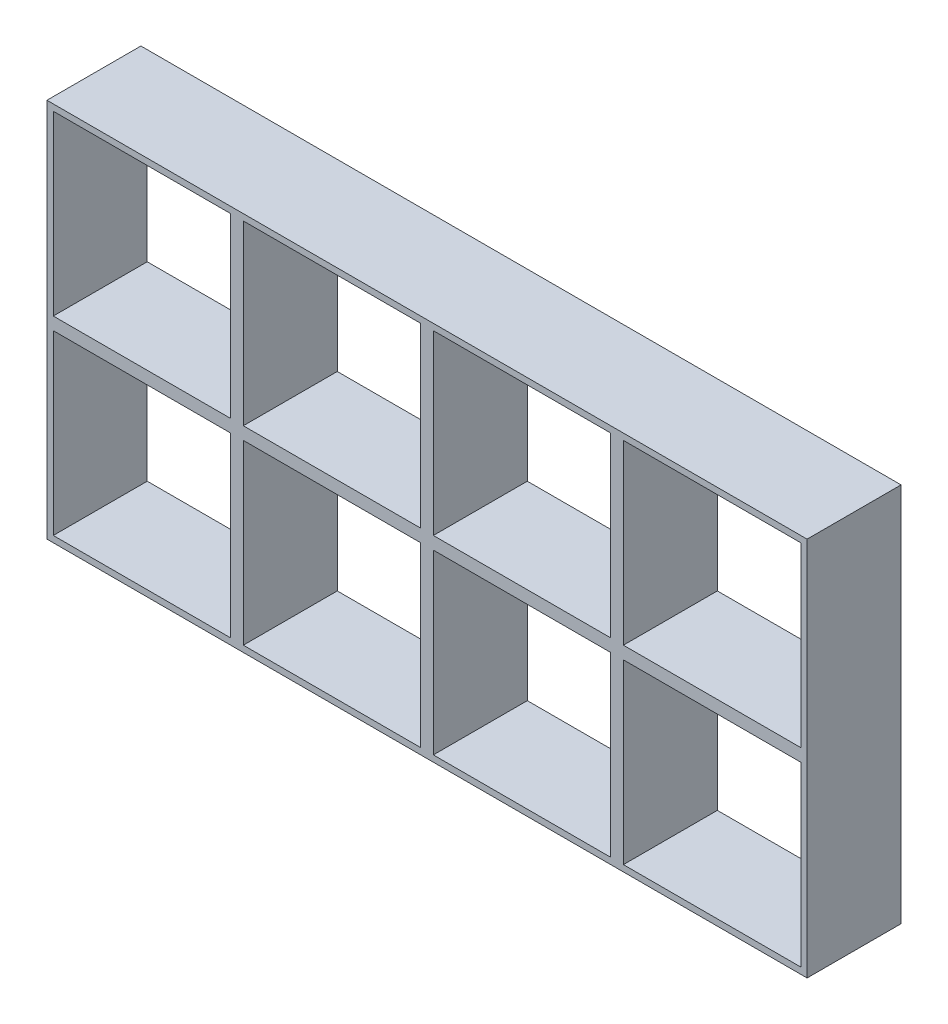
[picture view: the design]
ISO-10303-21;
HEADER;
FILE_DESCRIPTION(('STEP AP214'),'2;1');
FILE_NAME('part.step','',(''),(''),'','','');
FILE_SCHEMA(('AUTOMOTIVE_DESIGN { 1 0 10303 214 1 1 1 1 }'));
ENDSEC;
DATA;
#1=APPLICATION_CONTEXT('core data for automotive mechanical design processes');
#2=APPLICATION_PROTOCOL_DEFINITION('international standard','automotive_design',2000,#1);
#3=PRODUCT_CONTEXT('',#1,'mechanical');
#4=PRODUCT('Part','Part','',(#3));
#5=PRODUCT_RELATED_PRODUCT_CATEGORY('part','',(#4));
#6=PRODUCT_DEFINITION_FORMATION('','',#4);
#7=PRODUCT_DEFINITION_CONTEXT('part definition',#1,'design');
#8=PRODUCT_DEFINITION('design','',#6,#7);
#9=PRODUCT_DEFINITION_SHAPE('','',#8);
#10=(LENGTH_UNIT() NAMED_UNIT(*) SI_UNIT(.MILLI.,.METRE.));
#11=(NAMED_UNIT(*) PLANE_ANGLE_UNIT() SI_UNIT($,.RADIAN.));
#12=(NAMED_UNIT(*) SI_UNIT($,.STERADIAN.) SOLID_ANGLE_UNIT());
#13=UNCERTAINTY_MEASURE_WITH_UNIT(LENGTH_MEASURE(1.E-05),#10,'distance_accuracy_value','');
#14=(GEOMETRIC_REPRESENTATION_CONTEXT(3) GLOBAL_UNCERTAINTY_ASSIGNED_CONTEXT((#13)) GLOBAL_UNIT_ASSIGNED_CONTEXT((#10,
#11,#12)) REPRESENTATION_CONTEXT('',''));
#15=CARTESIAN_POINT('',(0.,0.,0.));
#16=DIRECTION('',(0.,0.,1.));
#17=DIRECTION('',(1.,0.,0.));
#18=AXIS2_PLACEMENT_3D('',#15,#16,#17);
#19=CARTESIAN_POINT('',(0.,0.,14.8333333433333));
#20=DIRECTION('',(-1.,0.,0.));
#21=DIRECTION('',(0.,0.,1.));
#22=AXIS2_PLACEMENT_3D('',#19,#20,#21);
#23=PLANE('',#22);
#24=DIRECTION('',(0.,1.,0.));
#25=VECTOR('',#24,1.);
#26=CARTESIAN_POINT('',(0.,0.,0.));
#27=LINE('',#26,#25);
#28=CARTESIAN_POINT('',(0.,-30.,0.));
#29=VERTEX_POINT('',#28);
#30=CARTESIAN_POINT('',(0.,30.,0.));
#31=VERTEX_POINT('',#30);
#32=EDGE_CURVE('E297',#29,#31,#27,.T.);
#33=ORIENTED_EDGE('',*,*,#32,.F.);
#34=DIRECTION('',(0.,0.,-1.));
#35=VECTOR('',#34,1.);
#36=CARTESIAN_POINT('',(0.,-30.,14.8333333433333));
#37=LINE('',#36,#35);
#38=CARTESIAN_POINT('',(0.,-30.,14.8333333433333));
#39=VERTEX_POINT('',#38);
#40=EDGE_CURVE('E240',#39,#29,#37,.T.);
#41=ORIENTED_EDGE('',*,*,#40,.F.);
#42=DIRECTION('',(0.,1.,0.));
#43=VECTOR('',#42,1.);
#44=CARTESIAN_POINT('',(0.,0.,14.8333333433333));
#45=LINE('',#44,#43);
#46=CARTESIAN_POINT('',(0.,30.,14.8333333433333));
#47=VERTEX_POINT('',#46);
#48=EDGE_CURVE('E218',#39,#47,#45,.T.);
#49=ORIENTED_EDGE('',*,*,#48,.T.);
#50=DIRECTION('',(0.,0.,-1.));
#51=VECTOR('',#50,1.);
#52=CARTESIAN_POINT('',(0.,30.,14.8333333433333));
#53=LINE('',#52,#51);
#54=EDGE_CURVE('E62',#47,#31,#53,.T.);
#55=ORIENTED_EDGE('',*,*,#54,.T.);
#56=EDGE_LOOP('',(#33,#41,#49,#55));
#57=FACE_BOUND('',#56,.T.);
#58=ADVANCED_FACE('F51',(#57),#23,.T.);
#59=CARTESIAN_POINT('',(120.,0.,14.8333333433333));
#60=DIRECTION('',(-1.,0.,0.));
#61=DIRECTION('',(0.,-1.,0.));
#62=AXIS2_PLACEMENT_3D('',#59,#60,#61);
#63=PLANE('',#62);
#64=DIRECTION('',(0.,1.,0.));
#65=VECTOR('',#64,1.);
#66=CARTESIAN_POINT('',(120.,0.,0.));
#67=LINE('',#66,#65);
#68=CARTESIAN_POINT('',(120.,-30.,0.));
#69=VERTEX_POINT('',#68);
#70=CARTESIAN_POINT('',(120.,30.,0.));
#71=VERTEX_POINT('',#70);
#72=EDGE_CURVE('E300',#69,#71,#67,.T.);
#73=ORIENTED_EDGE('',*,*,#72,.T.);
#74=DIRECTION('',(0.,0.,-1.));
#75=VECTOR('',#74,1.);
#76=CARTESIAN_POINT('',(120.,30.,14.8333333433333));
#77=LINE('',#76,#75);
#78=CARTESIAN_POINT('',(120.,30.,14.8333333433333));
#79=VERTEX_POINT('',#78);
#80=EDGE_CURVE('E11',#79,#71,#77,.T.);
#81=ORIENTED_EDGE('',*,*,#80,.F.);
#82=DIRECTION('',(0.,1.,0.));
#83=VECTOR('',#82,1.);
#84=CARTESIAN_POINT('',(120.,0.,14.8333333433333));
#85=LINE('',#84,#83);
#86=CARTESIAN_POINT('',(120.,-30.,14.8333333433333));
#87=VERTEX_POINT('',#86);
#88=EDGE_CURVE('E223',#87,#79,#85,.T.);
#89=ORIENTED_EDGE('',*,*,#88,.F.);
#90=DIRECTION('',(0.,0.,-1.));
#91=VECTOR('',#90,1.);
#92=CARTESIAN_POINT('',(120.,-30.,14.8333333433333));
#93=LINE('',#92,#91);
#94=EDGE_CURVE('E488',#87,#69,#93,.T.);
#95=ORIENTED_EDGE('',*,*,#94,.T.);
#96=EDGE_LOOP('',(#73,#81,#89,#95));
#97=FACE_BOUND('',#96,.T.);
#98=ADVANCED_FACE('F743',(#97),#63,.F.);
#99=CARTESIAN_POINT('',(0.,1.,14.8333333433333));
#100=DIRECTION('',(0.,1.,0.));
#101=DIRECTION('',(0.,0.,1.));
#102=AXIS2_PLACEMENT_3D('',#99,#100,#101);
#103=PLANE('',#102);
#104=DIRECTION('',(1.,0.,0.));
#105=VECTOR('',#104,1.);
#106=CARTESIAN_POINT('',(0.,1.,0.));
#107=LINE('',#106,#105);
#108=CARTESIAN_POINT('',(1.,1.,0.));
#109=VERTEX_POINT('',#108);
#110=CARTESIAN_POINT('',(29.,1.,0.));
#111=VERTEX_POINT('',#110);
#112=EDGE_CURVE('E284',#109,#111,#107,.T.);
#113=ORIENTED_EDGE('',*,*,#112,.F.);
#114=DIRECTION('',(0.,0.,-1.));
#115=VECTOR('',#114,1.);
#116=CARTESIAN_POINT('',(1.,1.,14.8333333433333));
#117=LINE('',#116,#115);
#118=CARTESIAN_POINT('',(1.,1.,14.8333333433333));
#119=VERTEX_POINT('',#118);
#120=EDGE_CURVE('E204',#119,#109,#117,.T.);
#121=ORIENTED_EDGE('',*,*,#120,.F.);
#122=DIRECTION('',(1.,0.,0.));
#123=VECTOR('',#122,1.);
#124=CARTESIAN_POINT('',(0.,1.,14.8333333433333));
#125=LINE('',#124,#123);
#126=CARTESIAN_POINT('',(29.,1.,14.8333333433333));
#127=VERTEX_POINT('',#126);
#128=EDGE_CURVE('E202',#119,#127,#125,.T.);
#129=ORIENTED_EDGE('',*,*,#128,.T.);
#130=DIRECTION('',(0.,0.,-1.));
#131=VECTOR('',#130,1.);
#132=CARTESIAN_POINT('',(29.,1.,14.8333333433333));
#133=LINE('',#132,#131);
#134=EDGE_CURVE('E187',#127,#111,#133,.T.);
#135=ORIENTED_EDGE('',*,*,#134,.T.);
#136=EDGE_LOOP('',(#113,#121,#129,#135));
#137=FACE_BOUND('',#136,.T.);
#138=ADVANCED_FACE('F203',(#137),#103,.T.);
#139=CARTESIAN_POINT('',(1.,0.,14.8333333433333));
#140=DIRECTION('',(1.,0.,0.));
#141=DIRECTION('',(0.,1.,0.));
#142=AXIS2_PLACEMENT_3D('',#139,#140,#141);
#143=PLANE('',#142);
#144=DIRECTION('',(0.,-1.,0.));
#145=VECTOR('',#144,1.);
#146=CARTESIAN_POINT('',(1.,0.,0.));
#147=LINE('',#146,#145);
#148=CARTESIAN_POINT('',(1.,29.,0.));
#149=VERTEX_POINT('',#148);
#150=EDGE_CURVE('E287',#149,#109,#147,.T.);
#151=ORIENTED_EDGE('',*,*,#150,.F.);
#152=DIRECTION('',(0.,0.,-1.));
#153=VECTOR('',#152,1.);
#154=CARTESIAN_POINT('',(1.,29.,14.8333333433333));
#155=LINE('',#154,#153);
#156=CARTESIAN_POINT('',(1.,29.,14.8333333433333));
#157=VERTEX_POINT('',#156);
#158=EDGE_CURVE('E312',#157,#149,#155,.T.);
#159=ORIENTED_EDGE('',*,*,#158,.F.);
#160=DIRECTION('',(0.,-1.,0.));
#161=VECTOR('',#160,1.);
#162=CARTESIAN_POINT('',(1.,0.,14.8333333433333));
#163=LINE('',#162,#161);
#164=EDGE_CURVE('E209',#157,#119,#163,.T.);
#165=ORIENTED_EDGE('',*,*,#164,.T.);
#166=ORIENTED_EDGE('',*,*,#120,.T.);
#167=EDGE_LOOP('',(#151,#159,#165,#166));
#168=FACE_BOUND('',#167,.T.);
#169=ADVANCED_FACE('F414',(#168),#143,.T.);
#170=CARTESIAN_POINT('',(0.,29.,14.8333333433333));
#171=DIRECTION('',(0.,-1.,0.));
#172=DIRECTION('',(1.,0.,0.));
#173=AXIS2_PLACEMENT_3D('',#170,#171,#172);
#174=PLANE('',#173);
#175=DIRECTION('',(-1.,0.,0.));
#176=VECTOR('',#175,1.);
#177=CARTESIAN_POINT('',(0.,29.,0.));
#178=LINE('',#177,#176);
#179=CARTESIAN_POINT('',(29.,29.,0.));
#180=VERTEX_POINT('',#179);
#181=EDGE_CURVE('E291',#180,#149,#178,.T.);
#182=ORIENTED_EDGE('',*,*,#181,.F.);
#183=DIRECTION('',(0.,0.,-1.));
#184=VECTOR('',#183,1.);
#185=CARTESIAN_POINT('',(29.,29.,14.8333333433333));
#186=LINE('',#185,#184);
#187=CARTESIAN_POINT('',(29.,29.,14.8333333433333));
#188=VERTEX_POINT('',#187);
#189=EDGE_CURVE('E198',#188,#180,#186,.T.);
#190=ORIENTED_EDGE('',*,*,#189,.F.);
#191=DIRECTION('',(-1.,0.,0.));
#192=VECTOR('',#191,1.);
#193=CARTESIAN_POINT('',(0.,29.,14.8333333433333));
#194=LINE('',#193,#192);
#195=EDGE_CURVE('E216',#188,#157,#194,.T.);
#196=ORIENTED_EDGE('',*,*,#195,.T.);
#197=ORIENTED_EDGE('',*,*,#158,.T.);
#198=EDGE_LOOP('',(#182,#190,#196,#197));
#199=FACE_BOUND('',#198,.T.);
#200=ADVANCED_FACE('F417',(#199),#174,.T.);
#201=CARTESIAN_POINT('',(0.,0.999999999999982,14.8333333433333));
#202=DIRECTION('',(0.,1.,0.));
#203=DIRECTION('',(-1.,0.,0.));
#204=AXIS2_PLACEMENT_3D('',#201,#202,#203);
#205=PLANE('',#204);
#206=DIRECTION('',(1.,0.,0.));
#207=VECTOR('',#206,1.);
#208=CARTESIAN_POINT('',(0.,0.999999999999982,0.));
#209=LINE('',#208,#207);
#210=CARTESIAN_POINT('',(91.,1.00000000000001,0.));
#211=VERTEX_POINT('',#210);
#212=CARTESIAN_POINT('',(119.,1.00000000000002,0.));
#213=VERTEX_POINT('',#212);
#214=EDGE_CURVE('E268',#211,#213,#209,.T.);
#215=ORIENTED_EDGE('',*,*,#214,.F.);
#216=DIRECTION('',(0.,0.,-1.));
#217=VECTOR('',#216,1.);
#218=CARTESIAN_POINT('',(91.,1.00000000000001,14.8333333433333));
#219=LINE('',#218,#217);
#220=CARTESIAN_POINT('',(91.,1.00000000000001,14.8333333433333));
#221=VERTEX_POINT('',#220);
#222=EDGE_CURVE('E199',#221,#211,#219,.T.);
#223=ORIENTED_EDGE('',*,*,#222,.F.);
#224=DIRECTION('',(1.,0.,0.));
#225=VECTOR('',#224,1.);
#226=CARTESIAN_POINT('',(0.,0.999999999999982,14.8333333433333));
#227=LINE('',#226,#225);
#228=CARTESIAN_POINT('',(119.,1.00000000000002,14.8333333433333));
#229=VERTEX_POINT('',#228);
#230=EDGE_CURVE('E397',#221,#229,#227,.T.);
#231=ORIENTED_EDGE('',*,*,#230,.T.);
#232=DIRECTION('',(0.,0.,-1.));
#233=VECTOR('',#232,1.);
#234=CARTESIAN_POINT('',(119.,1.00000000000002,14.8333333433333));
#235=LINE('',#234,#233);
#236=EDGE_CURVE('E317',#229,#213,#235,.T.);
#237=ORIENTED_EDGE('',*,*,#236,.T.);
#238=EDGE_LOOP('',(#215,#223,#231,#237));
#239=FACE_BOUND('',#238,.T.);
#240=ADVANCED_FACE('F756',(#239),#205,.T.);
#241=CARTESIAN_POINT('',(91.,0.,14.8333333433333));
#242=DIRECTION('',(-1.,0.,0.));
#243=DIRECTION('',(0.,0.,1.));
#244=AXIS2_PLACEMENT_3D('',#241,#242,#243);
#245=PLANE('',#244);
#246=DIRECTION('',(0.,1.,0.));
#247=VECTOR('',#246,1.);
#248=CARTESIAN_POINT('',(91.,0.,0.));
#249=LINE('',#248,#247);
#250=CARTESIAN_POINT('',(91.,29.,0.));
#251=VERTEX_POINT('',#250);
#252=EDGE_CURVE('E272',#211,#251,#249,.T.);
#253=ORIENTED_EDGE('',*,*,#252,.T.);
#254=DIRECTION('',(0.,0.,-1.));
#255=VECTOR('',#254,1.);
#256=CARTESIAN_POINT('',(91.,29.,14.8333333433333));
#257=LINE('',#256,#255);
#258=CARTESIAN_POINT('',(91.,29.,14.8333333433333));
#259=VERTEX_POINT('',#258);
#260=EDGE_CURVE('E325',#259,#251,#257,.T.);
#261=ORIENTED_EDGE('',*,*,#260,.F.);
#262=DIRECTION('',(0.,1.,0.));
#263=VECTOR('',#262,1.);
#264=CARTESIAN_POINT('',(91.,0.,14.8333333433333));
#265=LINE('',#264,#263);
#266=EDGE_CURVE('E401',#221,#259,#265,.T.);
#267=ORIENTED_EDGE('',*,*,#266,.F.);
#268=ORIENTED_EDGE('',*,*,#222,.T.);
#269=EDGE_LOOP('',(#253,#261,#267,#268));
#270=FACE_BOUND('',#269,.T.);
#271=ADVANCED_FACE('F769',(#270),#245,.F.);
#272=CARTESIAN_POINT('',(0.,29.,14.8333333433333));
#273=DIRECTION('',(0.,1.,0.));
#274=DIRECTION('',(-1.,0.,0.));
#275=AXIS2_PLACEMENT_3D('',#272,#273,#274);
#276=PLANE('',#275);
#277=DIRECTION('',(1.,0.,0.));
#278=VECTOR('',#277,1.);
#279=CARTESIAN_POINT('',(0.,29.,0.));
#280=LINE('',#279,#278);
#281=CARTESIAN_POINT('',(119.,29.,0.));
#282=VERTEX_POINT('',#281);
#283=EDGE_CURVE('E276',#251,#282,#280,.T.);
#284=ORIENTED_EDGE('',*,*,#283,.T.);
#285=DIRECTION('',(0.,0.,-1.));
#286=VECTOR('',#285,1.);
#287=CARTESIAN_POINT('',(119.,29.,14.8333333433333));
#288=LINE('',#287,#286);
#289=CARTESIAN_POINT('',(119.,29.,14.8333333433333));
#290=VERTEX_POINT('',#289);
#291=EDGE_CURVE('E320',#290,#282,#288,.T.);
#292=ORIENTED_EDGE('',*,*,#291,.F.);
#293=DIRECTION('',(1.,0.,0.));
#294=VECTOR('',#293,1.);
#295=CARTESIAN_POINT('',(0.,29.,14.8333333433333));
#296=LINE('',#295,#294);
#297=EDGE_CURVE('E405',#259,#290,#296,.T.);
#298=ORIENTED_EDGE('',*,*,#297,.F.);
#299=ORIENTED_EDGE('',*,*,#260,.T.);
#300=EDGE_LOOP('',(#284,#292,#298,#299));
#301=FACE_BOUND('',#300,.T.);
#302=ADVANCED_FACE('F765',(#301),#276,.F.);
#303=CARTESIAN_POINT('',(0.,0.999999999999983,14.8333333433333));
#304=DIRECTION('',(0.,1.,0.));
#305=DIRECTION('',(-1.,0.,0.));
#306=AXIS2_PLACEMENT_3D('',#303,#304,#305);
#307=PLANE('',#306);
#308=DIRECTION('',(1.,0.,0.));
#309=VECTOR('',#308,1.);
#310=CARTESIAN_POINT('',(0.,0.999999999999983,0.));
#311=LINE('',#310,#309);
#312=CARTESIAN_POINT('',(61.,1.,0.));
#313=VERTEX_POINT('',#312);
#314=CARTESIAN_POINT('',(89.,1.00000000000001,0.));
#315=VERTEX_POINT('',#314);
#316=EDGE_CURVE('E252',#313,#315,#311,.T.);
#317=ORIENTED_EDGE('',*,*,#316,.F.);
#318=DIRECTION('',(0.,0.,-1.));
#319=VECTOR('',#318,1.);
#320=CARTESIAN_POINT('',(61.,1.,14.8333333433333));
#321=LINE('',#320,#319);
#322=CARTESIAN_POINT('',(61.,1.,14.8333333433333));
#323=VERTEX_POINT('',#322);
#324=EDGE_CURVE('E321',#323,#313,#321,.T.);
#325=ORIENTED_EDGE('',*,*,#324,.F.);
#326=DIRECTION('',(1.,0.,0.));
#327=VECTOR('',#326,1.);
#328=CARTESIAN_POINT('',(0.,0.999999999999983,14.8333333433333));
#329=LINE('',#328,#327);
#330=CARTESIAN_POINT('',(89.,1.00000000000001,14.8333333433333));
#331=VERTEX_POINT('',#330);
#332=EDGE_CURVE('E377',#323,#331,#329,.T.);
#333=ORIENTED_EDGE('',*,*,#332,.T.);
#334=DIRECTION('',(0.,0.,-1.));
#335=VECTOR('',#334,1.);
#336=CARTESIAN_POINT('',(89.,1.00000000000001,14.8333333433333));
#337=LINE('',#336,#335);
#338=EDGE_CURVE('E331',#331,#315,#337,.T.);
#339=ORIENTED_EDGE('',*,*,#338,.T.);
#340=EDGE_LOOP('',(#317,#325,#333,#339));
#341=FACE_BOUND('',#340,.T.);
#342=ADVANCED_FACE('F768',(#341),#307,.T.);
#343=CARTESIAN_POINT('',(61.,0.,14.8333333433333));
#344=DIRECTION('',(-1.,0.,0.));
#345=DIRECTION('',(0.,-1.,0.));
#346=AXIS2_PLACEMENT_3D('',#343,#344,#345);
#347=PLANE('',#346);
#348=DIRECTION('',(0.,1.,0.));
#349=VECTOR('',#348,1.);
#350=CARTESIAN_POINT('',(61.,0.,0.));
#351=LINE('',#350,#349);
#352=CARTESIAN_POINT('',(61.,29.,0.));
#353=VERTEX_POINT('',#352);
#354=EDGE_CURVE('E256',#313,#353,#351,.T.);
#355=ORIENTED_EDGE('',*,*,#354,.T.);
#356=DIRECTION('',(0.,0.,-1.));
#357=VECTOR('',#356,1.);
#358=CARTESIAN_POINT('',(61.,29.,14.8333333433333));
#359=LINE('',#358,#357);
#360=CARTESIAN_POINT('',(61.,29.,14.8333333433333));
#361=VERTEX_POINT('',#360);
#362=EDGE_CURVE('E338',#361,#353,#359,.T.);
#363=ORIENTED_EDGE('',*,*,#362,.F.);
#364=DIRECTION('',(0.,1.,0.));
#365=VECTOR('',#364,1.);
#366=CARTESIAN_POINT('',(61.,0.,14.8333333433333));
#367=LINE('',#366,#365);
#368=EDGE_CURVE('E383',#323,#361,#367,.T.);
#369=ORIENTED_EDGE('',*,*,#368,.F.);
#370=ORIENTED_EDGE('',*,*,#324,.T.);
#371=EDGE_LOOP('',(#355,#363,#369,#370));
#372=FACE_BOUND('',#371,.T.);
#373=ADVANCED_FACE('F783',(#372),#347,.F.);
#374=CARTESIAN_POINT('',(0.,29.,14.8333333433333));
#375=DIRECTION('',(0.,1.,0.));
#376=DIRECTION('',(0.,0.,1.));
#377=AXIS2_PLACEMENT_3D('',#374,#375,#376);
#378=PLANE('',#377);
#379=DIRECTION('',(1.,0.,0.));
#380=VECTOR('',#379,1.);
#381=CARTESIAN_POINT('',(0.,29.,0.));
#382=LINE('',#381,#380);
#383=CARTESIAN_POINT('',(89.,29.,0.));
#384=VERTEX_POINT('',#383);
#385=EDGE_CURVE('E260',#353,#384,#382,.T.);
#386=ORIENTED_EDGE('',*,*,#385,.T.);
#387=DIRECTION('',(0.,0.,-1.));
#388=VECTOR('',#387,1.);
#389=CARTESIAN_POINT('',(89.,29.,14.8333333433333));
#390=LINE('',#389,#388);
#391=CARTESIAN_POINT('',(89.,29.,14.8333333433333));
#392=VERTEX_POINT('',#391);
#393=EDGE_CURVE('E334',#392,#384,#390,.T.);
#394=ORIENTED_EDGE('',*,*,#393,.F.);
#395=DIRECTION('',(1.,0.,0.));
#396=VECTOR('',#395,1.);
#397=CARTESIAN_POINT('',(0.,29.,14.8333333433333));
#398=LINE('',#397,#396);
#399=EDGE_CURVE('E390',#361,#392,#398,.T.);
#400=ORIENTED_EDGE('',*,*,#399,.F.);
#401=ORIENTED_EDGE('',*,*,#362,.T.);
#402=EDGE_LOOP('',(#386,#394,#400,#401));
#403=FACE_BOUND('',#402,.T.);
#404=ADVANCED_FACE('F780',(#403),#378,.F.);
#405=CARTESIAN_POINT('',(0.,1.,14.8333333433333));
#406=DIRECTION('',(0.,1.,0.));
#407=DIRECTION('',(-1.,0.,0.));
#408=AXIS2_PLACEMENT_3D('',#405,#406,#407);
#409=PLANE('',#408);
#410=DIRECTION('',(1.,0.,0.));
#411=VECTOR('',#410,1.);
#412=CARTESIAN_POINT('',(0.,1.,0.));
#413=LINE('',#412,#411);
#414=CARTESIAN_POINT('',(31.,1.,0.));
#415=VERTEX_POINT('',#414);
#416=CARTESIAN_POINT('',(59.,1.,0.));
#417=VERTEX_POINT('',#416);
#418=EDGE_CURVE('E235',#415,#417,#413,.T.);
#419=ORIENTED_EDGE('',*,*,#418,.F.);
#420=DIRECTION('',(0.,0.,-1.));
#421=VECTOR('',#420,1.);
#422=CARTESIAN_POINT('',(31.,1.,14.8333333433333));
#423=LINE('',#422,#421);
#424=CARTESIAN_POINT('',(31.,1.,14.8333333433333));
#425=VERTEX_POINT('',#424);
#426=EDGE_CURVE('E55',#425,#415,#423,.T.);
#427=ORIENTED_EDGE('',*,*,#426,.F.);
#428=DIRECTION('',(1.,0.,0.));
#429=VECTOR('',#428,1.);
#430=CARTESIAN_POINT('',(0.,1.,14.8333333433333));
#431=LINE('',#430,#429);
#432=CARTESIAN_POINT('',(59.,1.,14.8333333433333));
#433=VERTEX_POINT('',#432);
#434=EDGE_CURVE('E307',#425,#433,#431,.T.);
#435=ORIENTED_EDGE('',*,*,#434,.T.);
#436=DIRECTION('',(0.,0.,-1.));
#437=VECTOR('',#436,1.);
#438=CARTESIAN_POINT('',(59.,1.,14.8333333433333));
#439=LINE('',#438,#437);
#440=EDGE_CURVE('E234',#433,#417,#439,.T.);
#441=ORIENTED_EDGE('',*,*,#440,.T.);
#442=EDGE_LOOP('',(#419,#427,#435,#441));
#443=FACE_BOUND('',#442,.T.);
#444=ADVANCED_FACE('F53',(#443),#409,.T.);
#445=CARTESIAN_POINT('',(31.,0.,14.8333333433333));
#446=DIRECTION('',(1.,0.,0.));
#447=DIRECTION('',(0.,1.,0.));
#448=AXIS2_PLACEMENT_3D('',#445,#446,#447);
#449=PLANE('',#448);
#450=DIRECTION('',(0.,-1.,0.));
#451=VECTOR('',#450,1.);
#452=CARTESIAN_POINT('',(31.,0.,0.));
#453=LINE('',#452,#451);
#454=CARTESIAN_POINT('',(31.,29.,0.));
#455=VERTEX_POINT('',#454);
#456=EDGE_CURVE('E239',#455,#415,#453,.T.);
#457=ORIENTED_EDGE('',*,*,#456,.F.);
#458=DIRECTION('',(0.,0.,-1.));
#459=VECTOR('',#458,1.);
#460=CARTESIAN_POINT('',(31.,29.,14.8333333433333));
#461=LINE('',#460,#459);
#462=CARTESIAN_POINT('',(31.,29.,14.8333333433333));
#463=VERTEX_POINT('',#462);
#464=EDGE_CURVE('E347',#463,#455,#461,.T.);
#465=ORIENTED_EDGE('',*,*,#464,.F.);
#466=DIRECTION('',(0.,-1.,0.));
#467=VECTOR('',#466,1.);
#468=CARTESIAN_POINT('',(31.,0.,14.8333333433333));
#469=LINE('',#468,#467);
#470=EDGE_CURVE('E360',#463,#425,#469,.T.);
#471=ORIENTED_EDGE('',*,*,#470,.T.);
#472=ORIENTED_EDGE('',*,*,#426,.T.);
#473=EDGE_LOOP('',(#457,#465,#471,#472));
#474=FACE_BOUND('',#473,.T.);
#475=ADVANCED_FACE('F358',(#474),#449,.T.);
#476=CARTESIAN_POINT('',(0.,29.,14.8333333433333));
#477=DIRECTION('',(0.,-1.,0.));
#478=DIRECTION('',(1.,0.,0.));
#479=AXIS2_PLACEMENT_3D('',#476,#477,#478);
#480=PLANE('',#479);
#481=DIRECTION('',(-1.,0.,0.));
#482=VECTOR('',#481,1.);
#483=CARTESIAN_POINT('',(0.,29.,0.));
#484=LINE('',#483,#482);
#485=CARTESIAN_POINT('',(59.,29.,0.));
#486=VERTEX_POINT('',#485);
#487=EDGE_CURVE('E244',#486,#455,#484,.T.);
#488=ORIENTED_EDGE('',*,*,#487,.F.);
#489=DIRECTION('',(0.,0.,-1.));
#490=VECTOR('',#489,1.);
#491=CARTESIAN_POINT('',(59.,29.,14.8333333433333));
#492=LINE('',#491,#490);
#493=CARTESIAN_POINT('',(59.,29.,14.8333333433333));
#494=VERTEX_POINT('',#493);
#495=EDGE_CURVE('E345',#494,#486,#492,.T.);
#496=ORIENTED_EDGE('',*,*,#495,.F.);
#497=DIRECTION('',(-1.,0.,0.));
#498=VECTOR('',#497,1.);
#499=CARTESIAN_POINT('',(0.,29.,14.8333333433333));
#500=LINE('',#499,#498);
#501=EDGE_CURVE('E367',#494,#463,#500,.T.);
#502=ORIENTED_EDGE('',*,*,#501,.T.);
#503=ORIENTED_EDGE('',*,*,#464,.T.);
#504=EDGE_LOOP('',(#488,#496,#502,#503));
#505=FACE_BOUND('',#504,.T.);
#506=ADVANCED_FACE('F365',(#505),#480,.T.);
#507=CARTESIAN_POINT('',(29.,0.,14.8333333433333));
#508=DIRECTION('',(-1.,0.,0.));
#509=DIRECTION('',(0.,0.,1.));
#510=AXIS2_PLACEMENT_3D('',#507,#508,#509);
#511=PLANE('',#510);
#512=DIRECTION('',(0.,1.,0.));
#513=VECTOR('',#512,1.);
#514=CARTESIAN_POINT('',(29.,0.,0.));
#515=LINE('',#514,#513);
#516=EDGE_CURVE('E193',#111,#180,#515,.T.);
#517=ORIENTED_EDGE('',*,*,#516,.F.);
#518=ORIENTED_EDGE('',*,*,#134,.F.);
#519=DIRECTION('',(0.,1.,0.));
#520=VECTOR('',#519,1.);
#521=CARTESIAN_POINT('',(29.,0.,14.8333333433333));
#522=LINE('',#521,#520);
#523=EDGE_CURVE('E191',#127,#188,#522,.T.);
#524=ORIENTED_EDGE('',*,*,#523,.T.);
#525=ORIENTED_EDGE('',*,*,#189,.T.);
#526=EDGE_LOOP('',(#517,#518,#524,#525));
#527=FACE_BOUND('',#526,.T.);
#528=ADVANCED_FACE('F189',(#527),#511,.T.);
#529=CARTESIAN_POINT('',(119.,0.,14.8333333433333));
#530=DIRECTION('',(1.,0.,0.));
#531=DIRECTION('',(0.,1.,0.));
#532=AXIS2_PLACEMENT_3D('',#529,#530,#531);
#533=PLANE('',#532);
#534=DIRECTION('',(0.,-1.,0.));
#535=VECTOR('',#534,1.);
#536=CARTESIAN_POINT('',(119.,0.,0.));
#537=LINE('',#536,#535);
#538=EDGE_CURVE('E280',#282,#213,#537,.T.);
#539=ORIENTED_EDGE('',*,*,#538,.T.);
#540=ORIENTED_EDGE('',*,*,#236,.F.);
#541=DIRECTION('',(0.,-1.,0.));
#542=VECTOR('',#541,1.);
#543=CARTESIAN_POINT('',(119.,0.,14.8333333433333));
#544=LINE('',#543,#542);
#545=EDGE_CURVE('E210',#290,#229,#544,.T.);
#546=ORIENTED_EDGE('',*,*,#545,.F.);
#547=ORIENTED_EDGE('',*,*,#291,.T.);
#548=EDGE_LOOP('',(#539,#540,#546,#547));
#549=FACE_BOUND('',#548,.T.);
#550=ADVANCED_FACE('F753',(#549),#533,.F.);
#551=CARTESIAN_POINT('',(89.,0.,14.8333333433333));
#552=DIRECTION('',(1.,0.,0.));
#553=DIRECTION('',(0.,0.,-1.));
#554=AXIS2_PLACEMENT_3D('',#551,#552,#553);
#555=PLANE('',#554);
#556=DIRECTION('',(0.,-1.,0.));
#557=VECTOR('',#556,1.);
#558=CARTESIAN_POINT('',(89.,0.,0.));
#559=LINE('',#558,#557);
#560=EDGE_CURVE('E264',#384,#315,#559,.T.);
#561=ORIENTED_EDGE('',*,*,#560,.T.);
#562=ORIENTED_EDGE('',*,*,#338,.F.);
#563=DIRECTION('',(0.,-1.,0.));
#564=VECTOR('',#563,1.);
#565=CARTESIAN_POINT('',(89.,0.,14.8333333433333));
#566=LINE('',#565,#564);
#567=EDGE_CURVE('E394',#392,#331,#566,.T.);
#568=ORIENTED_EDGE('',*,*,#567,.F.);
#569=ORIENTED_EDGE('',*,*,#393,.T.);
#570=EDGE_LOOP('',(#561,#562,#568,#569));
#571=FACE_BOUND('',#570,.T.);
#572=ADVANCED_FACE('F763',(#571),#555,.F.);
#573=CARTESIAN_POINT('',(59.,0.,14.8333333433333));
#574=DIRECTION('',(-1.,0.,0.));
#575=DIRECTION('',(0.,0.,1.));
#576=AXIS2_PLACEMENT_3D('',#573,#574,#575);
#577=PLANE('',#576);
#578=DIRECTION('',(0.,1.,0.));
#579=VECTOR('',#578,1.);
#580=CARTESIAN_POINT('',(59.,0.,0.));
#581=LINE('',#580,#579);
#582=EDGE_CURVE('E248',#417,#486,#581,.T.);
#583=ORIENTED_EDGE('',*,*,#582,.F.);
#584=ORIENTED_EDGE('',*,*,#440,.F.);
#585=DIRECTION('',(0.,1.,0.));
#586=VECTOR('',#585,1.);
#587=CARTESIAN_POINT('',(59.,0.,14.8333333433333));
#588=LINE('',#587,#586);
#589=EDGE_CURVE('E373',#433,#494,#588,.T.);
#590=ORIENTED_EDGE('',*,*,#589,.T.);
#591=ORIENTED_EDGE('',*,*,#495,.T.);
#592=EDGE_LOOP('',(#583,#584,#590,#591));
#593=FACE_BOUND('',#592,.T.);
#594=ADVANCED_FACE('F375',(#593),#577,.T.);
#595=CARTESIAN_POINT('',(0.,30.,14.8333333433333));
#596=DIRECTION('',(0.,1.,0.));
#597=DIRECTION('',(-1.,0.,0.));
#598=AXIS2_PLACEMENT_3D('',#595,#596,#597);
#599=PLANE('',#598);
#600=DIRECTION('',(1.,0.,0.));
#601=VECTOR('',#600,1.);
#602=CARTESIAN_POINT('',(0.,30.,0.));
#603=LINE('',#602,#601);
#604=EDGE_CURVE('E303',#31,#71,#603,.T.);
#605=ORIENTED_EDGE('',*,*,#604,.F.);
#606=ORIENTED_EDGE('',*,*,#54,.F.);
#607=DIRECTION('',(1.,0.,0.));
#608=VECTOR('',#607,1.);
#609=CARTESIAN_POINT('',(0.,30.,14.8333333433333));
#610=LINE('',#609,#608);
#611=EDGE_CURVE('E231',#47,#79,#610,.T.);
#612=ORIENTED_EDGE('',*,*,#611,.T.);
#613=ORIENTED_EDGE('',*,*,#80,.T.);
#614=EDGE_LOOP('',(#605,#606,#612,#613));
#615=FACE_BOUND('',#614,.T.);
#616=ADVANCED_FACE('F793',(#615),#599,.T.);
#617=CARTESIAN_POINT('',(0.,0.,14.8333333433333));
#618=DIRECTION('',(0.,0.,1.));
#619=DIRECTION('',(1.,0.,0.));
#620=AXIS2_PLACEMENT_3D('',#617,#618,#619);
#621=PLANE('',#620);
#622=ORIENTED_EDGE('',*,*,#434,.F.);
#623=ORIENTED_EDGE('',*,*,#470,.F.);
#624=ORIENTED_EDGE('',*,*,#501,.F.);
#625=ORIENTED_EDGE('',*,*,#589,.F.);
#626=EDGE_LOOP('',(#622,#623,#624,#625));
#627=FACE_BOUND('',#626,.T.);
#628=ORIENTED_EDGE('',*,*,#332,.F.);
#629=ORIENTED_EDGE('',*,*,#368,.T.);
#630=ORIENTED_EDGE('',*,*,#399,.T.);
#631=ORIENTED_EDGE('',*,*,#567,.T.);
#632=EDGE_LOOP('',(#628,#629,#630,#631));
#633=FACE_BOUND('',#632,.T.);
#634=ORIENTED_EDGE('',*,*,#230,.F.);
#635=ORIENTED_EDGE('',*,*,#266,.T.);
#636=ORIENTED_EDGE('',*,*,#297,.T.);
#637=ORIENTED_EDGE('',*,*,#545,.T.);
#638=EDGE_LOOP('',(#634,#635,#636,#637));
#639=FACE_BOUND('',#638,.T.);
#640=ORIENTED_EDGE('',*,*,#128,.F.);
#641=ORIENTED_EDGE('',*,*,#164,.F.);
#642=ORIENTED_EDGE('',*,*,#195,.F.);
#643=ORIENTED_EDGE('',*,*,#523,.F.);
#644=EDGE_LOOP('',(#640,#641,#642,#643));
#645=FACE_BOUND('',#644,.T.);
#646=ORIENTED_EDGE('',*,*,#48,.F.);
#647=DIRECTION('',(1.,0.,0.));
#648=VECTOR('',#647,1.);
#649=CARTESIAN_POINT('',(0.,-30.,14.8333333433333));
#650=LINE('',#649,#648);
#651=EDGE_CURVE('E546',#39,#87,#650,.T.);
#652=ORIENTED_EDGE('',*,*,#651,.T.);
#653=ORIENTED_EDGE('',*,*,#88,.T.);
#654=ORIENTED_EDGE('',*,*,#611,.F.);
#655=EDGE_LOOP('',(#646,#652,#653,#654));
#656=FACE_BOUND('',#655,.T.);
#657=DIRECTION('',(1.,0.,0.));
#658=VECTOR('',#657,1.);
#659=CARTESIAN_POINT('',(0.,-1.,14.8333333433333));
#660=LINE('',#659,#658);
#661=CARTESIAN_POINT('',(31.,-0.999999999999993,14.8333333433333));
#662=VERTEX_POINT('',#661);
#663=CARTESIAN_POINT('',(59.,-0.999999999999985,14.8333333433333));
#664=VERTEX_POINT('',#663);
#665=EDGE_CURVE('E487',#662,#664,#660,.T.);
#666=ORIENTED_EDGE('',*,*,#665,.T.);
#667=DIRECTION('',(0.,-1.,0.));
#668=VECTOR('',#667,1.);
#669=CARTESIAN_POINT('',(59.,0.,14.8333333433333));
#670=LINE('',#669,#668);
#671=CARTESIAN_POINT('',(59.,-29.,14.8333333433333));
#672=VERTEX_POINT('',#671);
#673=EDGE_CURVE('E629',#664,#672,#670,.T.);
#674=ORIENTED_EDGE('',*,*,#673,.T.);
#675=DIRECTION('',(-1.,0.,0.));
#676=VECTOR('',#675,1.);
#677=CARTESIAN_POINT('',(0.,-29.,14.8333333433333));
#678=LINE('',#677,#676);
#679=CARTESIAN_POINT('',(31.,-29.,14.8333333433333));
#680=VERTEX_POINT('',#679);
#681=EDGE_CURVE('E1143',#672,#680,#678,.T.);
#682=ORIENTED_EDGE('',*,*,#681,.T.);
#683=DIRECTION('',(0.,1.,0.));
#684=VECTOR('',#683,1.);
#685=CARTESIAN_POINT('',(31.,0.,14.8333333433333));
#686=LINE('',#685,#684);
#687=EDGE_CURVE('E730',#680,#662,#686,.T.);
#688=ORIENTED_EDGE('',*,*,#687,.T.);
#689=EDGE_LOOP('',(#666,#674,#682,#688));
#690=FACE_BOUND('',#689,.T.);
#691=DIRECTION('',(1.,0.,0.));
#692=VECTOR('',#691,1.);
#693=CARTESIAN_POINT('',(0.,-0.999999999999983,14.8333333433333));
#694=LINE('',#693,#692);
#695=CARTESIAN_POINT('',(61.,-0.999999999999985,14.8333333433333));
#696=VERTEX_POINT('',#695);
#697=CARTESIAN_POINT('',(89.,-0.999999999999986,14.8333333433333));
#698=VERTEX_POINT('',#697);
#699=EDGE_CURVE('E1129',#696,#698,#694,.T.);
#700=ORIENTED_EDGE('',*,*,#699,.T.);
#701=DIRECTION('',(0.,1.,0.));
#702=VECTOR('',#701,1.);
#703=CARTESIAN_POINT('',(89.,0.,14.8333333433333));
#704=LINE('',#703,#702);
#705=CARTESIAN_POINT('',(89.,-29.,14.8333333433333));
#706=VERTEX_POINT('',#705);
#707=EDGE_CURVE('E1128',#706,#698,#704,.T.);
#708=ORIENTED_EDGE('',*,*,#707,.F.);
#709=DIRECTION('',(1.,0.,0.));
#710=VECTOR('',#709,1.);
#711=CARTESIAN_POINT('',(0.,-29.,14.8333333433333));
#712=LINE('',#711,#710);
#713=CARTESIAN_POINT('',(61.,-29.,14.8333333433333));
#714=VERTEX_POINT('',#713);
#715=EDGE_CURVE('E1124',#714,#706,#712,.T.);
#716=ORIENTED_EDGE('',*,*,#715,.F.);
#717=DIRECTION('',(0.,-1.,0.));
#718=VECTOR('',#717,1.);
#719=CARTESIAN_POINT('',(61.,0.,14.8333333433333));
#720=LINE('',#719,#718);
#721=EDGE_CURVE('E1134',#696,#714,#720,.T.);
#722=ORIENTED_EDGE('',*,*,#721,.F.);
#723=EDGE_LOOP('',(#700,#708,#716,#722));
#724=FACE_BOUND('',#723,.T.);
#725=DIRECTION('',(1.,0.,0.));
#726=VECTOR('',#725,1.);
#727=CARTESIAN_POINT('',(0.,-0.999999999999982,14.8333333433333));
#728=LINE('',#727,#726);
#729=CARTESIAN_POINT('',(91.,-0.999999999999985,14.8333333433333));
#730=VERTEX_POINT('',#729);
#731=CARTESIAN_POINT('',(119.,-0.999999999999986,14.8333333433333));
#732=VERTEX_POINT('',#731);
#733=EDGE_CURVE('E697',#730,#732,#728,.T.);
#734=ORIENTED_EDGE('',*,*,#733,.T.);
#735=DIRECTION('',(0.,1.,0.));
#736=VECTOR('',#735,1.);
#737=CARTESIAN_POINT('',(119.,0.,14.8333333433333));
#738=LINE('',#737,#736);
#739=CARTESIAN_POINT('',(119.,-29.,14.8333333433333));
#740=VERTEX_POINT('',#739);
#741=EDGE_CURVE('E693',#740,#732,#738,.T.);
#742=ORIENTED_EDGE('',*,*,#741,.F.);
#743=DIRECTION('',(1.,0.,0.));
#744=VECTOR('',#743,1.);
#745=CARTESIAN_POINT('',(0.,-29.,14.8333333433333));
#746=LINE('',#745,#744);
#747=CARTESIAN_POINT('',(91.,-29.,14.8333333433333));
#748=VERTEX_POINT('',#747);
#749=EDGE_CURVE('E704',#748,#740,#746,.T.);
#750=ORIENTED_EDGE('',*,*,#749,.F.);
#751=DIRECTION('',(0.,-1.,0.));
#752=VECTOR('',#751,1.);
#753=CARTESIAN_POINT('',(91.,0.,14.8333333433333));
#754=LINE('',#753,#752);
#755=EDGE_CURVE('E700',#730,#748,#754,.T.);
#756=ORIENTED_EDGE('',*,*,#755,.F.);
#757=EDGE_LOOP('',(#734,#742,#750,#756));
#758=FACE_BOUND('',#757,.T.);
#759=DIRECTION('',(1.,0.,0.));
#760=VECTOR('',#759,1.);
#761=CARTESIAN_POINT('',(0.,-1.,14.8333333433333));
#762=LINE('',#761,#760);
#763=CARTESIAN_POINT('',(1.,-1.,14.8333333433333));
#764=VERTEX_POINT('',#763);
#765=CARTESIAN_POINT('',(29.,-0.999999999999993,14.8333333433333));
#766=VERTEX_POINT('',#765);
#767=EDGE_CURVE('E703',#764,#766,#762,.T.);
#768=ORIENTED_EDGE('',*,*,#767,.T.);
#769=DIRECTION('',(0.,-1.,0.));
#770=VECTOR('',#769,1.);
#771=CARTESIAN_POINT('',(29.,0.,14.8333333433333));
#772=LINE('',#771,#770);
#773=CARTESIAN_POINT('',(29.,-29.,14.8333333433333));
#774=VERTEX_POINT('',#773);
#775=EDGE_CURVE('E567',#766,#774,#772,.T.);
#776=ORIENTED_EDGE('',*,*,#775,.T.);
#777=DIRECTION('',(-1.,0.,0.));
#778=VECTOR('',#777,1.);
#779=CARTESIAN_POINT('',(0.,-29.,14.8333333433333));
#780=LINE('',#779,#778);
#781=CARTESIAN_POINT('',(1.00000000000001,-29.,14.8333333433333));
#782=VERTEX_POINT('',#781);
#783=EDGE_CURVE('E564',#774,#782,#780,.T.);
#784=ORIENTED_EDGE('',*,*,#783,.T.);
#785=DIRECTION('',(0.,1.,0.));
#786=VECTOR('',#785,1.);
#787=CARTESIAN_POINT('',(1.,0.,14.8333333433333));
#788=LINE('',#787,#786);
#789=EDGE_CURVE('E566',#782,#764,#788,.T.);
#790=ORIENTED_EDGE('',*,*,#789,.T.);
#791=EDGE_LOOP('',(#768,#776,#784,#790));
#792=FACE_BOUND('',#791,.T.);
#793=ADVANCED_FACE('F213',(#627,#633,#639,#645,#656,#690,#724,#758,#792),#621,.T.);
#794=CARTESIAN_POINT('',(0.,0.,0.));
#795=DIRECTION('',(0.,0.,1.));
#796=DIRECTION('',(1.,0.,0.));
#797=AXIS2_PLACEMENT_3D('',#794,#795,#796);
#798=PLANE('',#797);
#799=ORIENTED_EDGE('',*,*,#418,.T.);
#800=ORIENTED_EDGE('',*,*,#582,.T.);
#801=ORIENTED_EDGE('',*,*,#487,.T.);
#802=ORIENTED_EDGE('',*,*,#456,.T.);
#803=EDGE_LOOP('',(#799,#800,#801,#802));
#804=FACE_BOUND('',#803,.T.);
#805=ORIENTED_EDGE('',*,*,#316,.T.);
#806=ORIENTED_EDGE('',*,*,#560,.F.);
#807=ORIENTED_EDGE('',*,*,#385,.F.);
#808=ORIENTED_EDGE('',*,*,#354,.F.);
#809=EDGE_LOOP('',(#805,#806,#807,#808));
#810=FACE_BOUND('',#809,.T.);
#811=ORIENTED_EDGE('',*,*,#214,.T.);
#812=ORIENTED_EDGE('',*,*,#538,.F.);
#813=ORIENTED_EDGE('',*,*,#283,.F.);
#814=ORIENTED_EDGE('',*,*,#252,.F.);
#815=EDGE_LOOP('',(#811,#812,#813,#814));
#816=FACE_BOUND('',#815,.T.);
#817=ORIENTED_EDGE('',*,*,#112,.T.);
#818=ORIENTED_EDGE('',*,*,#516,.T.);
#819=ORIENTED_EDGE('',*,*,#181,.T.);
#820=ORIENTED_EDGE('',*,*,#150,.T.);
#821=EDGE_LOOP('',(#817,#818,#819,#820));
#822=FACE_BOUND('',#821,.T.);
#823=ORIENTED_EDGE('',*,*,#32,.T.);
#824=ORIENTED_EDGE('',*,*,#604,.T.);
#825=ORIENTED_EDGE('',*,*,#72,.F.);
#826=DIRECTION('',(1.,0.,0.));
#827=VECTOR('',#826,1.);
#828=CARTESIAN_POINT('',(0.,-30.,0.));
#829=LINE('',#828,#827);
#830=EDGE_CURVE('E483',#29,#69,#829,.T.);
#831=ORIENTED_EDGE('',*,*,#830,.F.);
#832=EDGE_LOOP('',(#823,#824,#825,#831));
#833=FACE_BOUND('',#832,.T.);
#834=DIRECTION('',(1.,0.,0.));
#835=VECTOR('',#834,1.);
#836=CARTESIAN_POINT('',(0.,-1.,0.));
#837=LINE('',#836,#835);
#838=CARTESIAN_POINT('',(31.,-0.999999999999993,0.));
#839=VERTEX_POINT('',#838);
#840=CARTESIAN_POINT('',(59.,-0.999999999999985,0.));
#841=VERTEX_POINT('',#840);
#842=EDGE_CURVE('E431',#839,#841,#837,.T.);
#843=ORIENTED_EDGE('',*,*,#842,.F.);
#844=DIRECTION('',(0.,1.,0.));
#845=VECTOR('',#844,1.);
#846=CARTESIAN_POINT('',(31.,0.,0.));
#847=LINE('',#846,#845);
#848=CARTESIAN_POINT('',(31.,-29.,0.));
#849=VERTEX_POINT('',#848);
#850=EDGE_CURVE('E571',#849,#839,#847,.T.);
#851=ORIENTED_EDGE('',*,*,#850,.F.);
#852=DIRECTION('',(-1.,0.,0.));
#853=VECTOR('',#852,1.);
#854=CARTESIAN_POINT('',(0.,-29.,0.));
#855=LINE('',#854,#853);
#856=CARTESIAN_POINT('',(59.,-29.,0.));
#857=VERTEX_POINT('',#856);
#858=EDGE_CURVE('E569',#857,#849,#855,.T.);
#859=ORIENTED_EDGE('',*,*,#858,.F.);
#860=DIRECTION('',(0.,-1.,0.));
#861=VECTOR('',#860,1.);
#862=CARTESIAN_POINT('',(59.,0.,0.));
#863=LINE('',#862,#861);
#864=EDGE_CURVE('E572',#841,#857,#863,.T.);
#865=ORIENTED_EDGE('',*,*,#864,.F.);
#866=EDGE_LOOP('',(#843,#851,#859,#865));
#867=FACE_BOUND('',#866,.T.);
#868=DIRECTION('',(1.,0.,0.));
#869=VECTOR('',#868,1.);
#870=CARTESIAN_POINT('',(0.,-0.999999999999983,0.));
#871=LINE('',#870,#869);
#872=CARTESIAN_POINT('',(61.,-0.999999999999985,0.));
#873=VERTEX_POINT('',#872);
#874=CARTESIAN_POINT('',(89.,-0.999999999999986,0.));
#875=VERTEX_POINT('',#874);
#876=EDGE_CURVE('E438',#873,#875,#871,.T.);
#877=ORIENTED_EDGE('',*,*,#876,.F.);
#878=DIRECTION('',(0.,-1.,0.));
#879=VECTOR('',#878,1.);
#880=CARTESIAN_POINT('',(61.,0.,0.));
#881=LINE('',#880,#879);
#882=CARTESIAN_POINT('',(61.,-29.,0.));
#883=VERTEX_POINT('',#882);
#884=EDGE_CURVE('E560',#873,#883,#881,.T.);
#885=ORIENTED_EDGE('',*,*,#884,.T.);
#886=DIRECTION('',(1.,0.,0.));
#887=VECTOR('',#886,1.);
#888=CARTESIAN_POINT('',(0.,-29.,0.));
#889=LINE('',#888,#887);
#890=CARTESIAN_POINT('',(89.,-29.,0.));
#891=VERTEX_POINT('',#890);
#892=EDGE_CURVE('E561',#883,#891,#889,.T.);
#893=ORIENTED_EDGE('',*,*,#892,.T.);
#894=DIRECTION('',(0.,1.,0.));
#895=VECTOR('',#894,1.);
#896=CARTESIAN_POINT('',(89.,0.,0.));
#897=LINE('',#896,#895);
#898=EDGE_CURVE('E587',#891,#875,#897,.T.);
#899=ORIENTED_EDGE('',*,*,#898,.T.);
#900=EDGE_LOOP('',(#877,#885,#893,#899));
#901=FACE_BOUND('',#900,.T.);
#902=DIRECTION('',(1.,0.,0.));
#903=VECTOR('',#902,1.);
#904=CARTESIAN_POINT('',(0.,-0.999999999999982,0.));
#905=LINE('',#904,#903);
#906=CARTESIAN_POINT('',(91.,-0.999999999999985,0.));
#907=VERTEX_POINT('',#906);
#908=CARTESIAN_POINT('',(119.,-0.999999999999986,0.));
#909=VERTEX_POINT('',#908);
#910=EDGE_CURVE('E446',#907,#909,#905,.T.);
#911=ORIENTED_EDGE('',*,*,#910,.F.);
#912=DIRECTION('',(0.,-1.,0.));
#913=VECTOR('',#912,1.);
#914=CARTESIAN_POINT('',(91.,0.,0.));
#915=LINE('',#914,#913);
#916=CARTESIAN_POINT('',(91.,-29.,0.));
#917=VERTEX_POINT('',#916);
#918=EDGE_CURVE('E468',#907,#917,#915,.T.);
#919=ORIENTED_EDGE('',*,*,#918,.T.);
#920=DIRECTION('',(1.,0.,0.));
#921=VECTOR('',#920,1.);
#922=CARTESIAN_POINT('',(0.,-29.,0.));
#923=LINE('',#922,#921);
#924=CARTESIAN_POINT('',(119.,-29.,0.));
#925=VERTEX_POINT('',#924);
#926=EDGE_CURVE('E474',#917,#925,#923,.T.);
#927=ORIENTED_EDGE('',*,*,#926,.T.);
#928=DIRECTION('',(0.,1.,0.));
#929=VECTOR('',#928,1.);
#930=CARTESIAN_POINT('',(119.,0.,0.));
#931=LINE('',#930,#929);
#932=EDGE_CURVE('E595',#925,#909,#931,.T.);
#933=ORIENTED_EDGE('',*,*,#932,.T.);
#934=EDGE_LOOP('',(#911,#919,#927,#933));
#935=FACE_BOUND('',#934,.T.);
#936=DIRECTION('',(1.,0.,0.));
#937=VECTOR('',#936,1.);
#938=CARTESIAN_POINT('',(0.,-1.,0.));
#939=LINE('',#938,#937);
#940=CARTESIAN_POINT('',(1.,-1.,0.));
#941=VERTEX_POINT('',#940);
#942=CARTESIAN_POINT('',(29.,-0.999999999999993,0.));
#943=VERTEX_POINT('',#942);
#944=EDGE_CURVE('E453',#941,#943,#939,.T.);
#945=ORIENTED_EDGE('',*,*,#944,.F.);
#946=DIRECTION('',(0.,1.,0.));
#947=VECTOR('',#946,1.);
#948=CARTESIAN_POINT('',(1.,0.,0.));
#949=LINE('',#948,#947);
#950=CARTESIAN_POINT('',(1.00000000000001,-29.,0.));
#951=VERTEX_POINT('',#950);
#952=EDGE_CURVE('E457',#951,#941,#949,.T.);
#953=ORIENTED_EDGE('',*,*,#952,.F.);
#954=DIRECTION('',(-1.,0.,0.));
#955=VECTOR('',#954,1.);
#956=CARTESIAN_POINT('',(0.,-29.,0.));
#957=LINE('',#956,#955);
#958=CARTESIAN_POINT('',(29.,-29.,0.));
#959=VERTEX_POINT('',#958);
#960=EDGE_CURVE('E471',#959,#951,#957,.T.);
#961=ORIENTED_EDGE('',*,*,#960,.F.);
#962=DIRECTION('',(0.,-1.,0.));
#963=VECTOR('',#962,1.);
#964=CARTESIAN_POINT('',(29.,0.,0.));
#965=LINE('',#964,#963);
#966=EDGE_CURVE('E460',#943,#959,#965,.T.);
#967=ORIENTED_EDGE('',*,*,#966,.F.);
#968=EDGE_LOOP('',(#945,#953,#961,#967));
#969=FACE_BOUND('',#968,.T.);
#970=ADVANCED_FACE('F363',(#804,#810,#816,#822,#833,#867,#901,#935,#969),#798,.F.);
#971=CARTESIAN_POINT('',(0.,-30.,14.8333333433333));
#972=DIRECTION('',(0.,1.,0.));
#973=DIRECTION('',(-1.,0.,0.));
#974=AXIS2_PLACEMENT_3D('',#971,#972,#973);
#975=PLANE('',#974);
#976=ORIENTED_EDGE('',*,*,#830,.T.);
#977=ORIENTED_EDGE('',*,*,#94,.F.);
#978=ORIENTED_EDGE('',*,*,#651,.F.);
#979=ORIENTED_EDGE('',*,*,#40,.T.);
#980=EDGE_LOOP('',(#976,#977,#978,#979));
#981=FACE_BOUND('',#980,.T.);
#982=ADVANCED_FACE('F421',(#981),#975,.F.);
#983=CARTESIAN_POINT('',(0.,-1.,14.8333333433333));
#984=DIRECTION('',(0.,1.,0.));
#985=DIRECTION('',(-1.,0.,0.));
#986=AXIS2_PLACEMENT_3D('',#983,#984,#985);
#987=PLANE('',#986);
#988=ORIENTED_EDGE('',*,*,#944,.T.);
#989=DIRECTION('',(0.,0.,-1.));
#990=VECTOR('',#989,1.);
#991=CARTESIAN_POINT('',(29.,-0.999999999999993,14.8333333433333));
#992=LINE('',#991,#990);
#993=EDGE_CURVE('E491',#766,#943,#992,.T.);
#994=ORIENTED_EDGE('',*,*,#993,.F.);
#995=ORIENTED_EDGE('',*,*,#767,.F.);
#996=DIRECTION('',(0.,0.,-1.));
#997=VECTOR('',#996,1.);
#998=CARTESIAN_POINT('',(1.,-1.,14.8333333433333));
#999=LINE('',#998,#997);
#1000=EDGE_CURVE('E495',#764,#941,#999,.T.);
#1001=ORIENTED_EDGE('',*,*,#1000,.T.);
#1002=EDGE_LOOP('',(#988,#994,#995,#1001));
#1003=FACE_BOUND('',#1002,.T.);
#1004=ADVANCED_FACE('F857',(#1003),#987,.F.);
#1005=CARTESIAN_POINT('',(29.,0.,14.8333333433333));
#1006=DIRECTION('',(1.,0.,0.));
#1007=DIRECTION('',(0.,1.,0.));
#1008=AXIS2_PLACEMENT_3D('',#1005,#1006,#1007);
#1009=PLANE('',#1008);
#1010=ORIENTED_EDGE('',*,*,#966,.T.);
#1011=DIRECTION('',(0.,0.,-1.));
#1012=VECTOR('',#1011,1.);
#1013=CARTESIAN_POINT('',(29.,-29.,14.8333333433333));
#1014=LINE('',#1013,#1012);
#1015=EDGE_CURVE('E503',#774,#959,#1014,.T.);
#1016=ORIENTED_EDGE('',*,*,#1015,.F.);
#1017=ORIENTED_EDGE('',*,*,#775,.F.);
#1018=ORIENTED_EDGE('',*,*,#993,.T.);
#1019=EDGE_LOOP('',(#1010,#1016,#1017,#1018));
#1020=FACE_BOUND('',#1019,.T.);
#1021=ADVANCED_FACE('F867',(#1020),#1009,.F.);
#1022=CARTESIAN_POINT('',(0.,-29.,14.8333333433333));
#1023=DIRECTION('',(0.,-1.,0.));
#1024=DIRECTION('',(1.,0.,0.));
#1025=AXIS2_PLACEMENT_3D('',#1022,#1023,#1024);
#1026=PLANE('',#1025);
#1027=ORIENTED_EDGE('',*,*,#960,.T.);
#1028=DIRECTION('',(0.,0.,-1.));
#1029=VECTOR('',#1028,1.);
#1030=CARTESIAN_POINT('',(1.00000000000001,-29.,14.8333333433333));
#1031=LINE('',#1030,#1029);
#1032=EDGE_CURVE('E498',#782,#951,#1031,.T.);
#1033=ORIENTED_EDGE('',*,*,#1032,.F.);
#1034=ORIENTED_EDGE('',*,*,#783,.F.);
#1035=ORIENTED_EDGE('',*,*,#1015,.T.);
#1036=EDGE_LOOP('',(#1027,#1033,#1034,#1035));
#1037=FACE_BOUND('',#1036,.T.);
#1038=ADVANCED_FACE('F876',(#1037),#1026,.F.);
#1039=CARTESIAN_POINT('',(0.,-0.999999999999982,14.8333333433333));
#1040=DIRECTION('',(0.,1.,0.));
#1041=DIRECTION('',(-1.,0.,0.));
#1042=AXIS2_PLACEMENT_3D('',#1039,#1040,#1041);
#1043=PLANE('',#1042);
#1044=ORIENTED_EDGE('',*,*,#910,.T.);
#1045=DIRECTION('',(0.,0.,-1.));
#1046=VECTOR('',#1045,1.);
#1047=CARTESIAN_POINT('',(119.,-0.999999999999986,14.8333333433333));
#1048=LINE('',#1047,#1046);
#1049=EDGE_CURVE('E499',#732,#909,#1048,.T.);
#1050=ORIENTED_EDGE('',*,*,#1049,.F.);
#1051=ORIENTED_EDGE('',*,*,#733,.F.);
#1052=DIRECTION('',(0.,0.,-1.));
#1053=VECTOR('',#1052,1.);
#1054=CARTESIAN_POINT('',(91.,-0.999999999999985,14.8333333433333));
#1055=LINE('',#1054,#1053);
#1056=EDGE_CURVE('E509',#730,#907,#1055,.T.);
#1057=ORIENTED_EDGE('',*,*,#1056,.T.);
#1058=EDGE_LOOP('',(#1044,#1050,#1051,#1057));
#1059=FACE_BOUND('',#1058,.T.);
#1060=ADVANCED_FACE('F696',(#1059),#1043,.F.);
#1061=CARTESIAN_POINT('',(119.,0.,14.8333333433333));
#1062=DIRECTION('',(-1.,0.,0.));
#1063=DIRECTION('',(0.,-1.,0.));
#1064=AXIS2_PLACEMENT_3D('',#1061,#1062,#1063);
#1065=PLANE('',#1064);
#1066=ORIENTED_EDGE('',*,*,#932,.F.);
#1067=DIRECTION('',(0.,0.,-1.));
#1068=VECTOR('',#1067,1.);
#1069=CARTESIAN_POINT('',(119.,-29.,14.8333333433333));
#1070=LINE('',#1069,#1068);
#1071=EDGE_CURVE('E518',#740,#925,#1070,.T.);
#1072=ORIENTED_EDGE('',*,*,#1071,.F.);
#1073=ORIENTED_EDGE('',*,*,#741,.T.);
#1074=ORIENTED_EDGE('',*,*,#1049,.T.);
#1075=EDGE_LOOP('',(#1066,#1072,#1073,#1074));
#1076=FACE_BOUND('',#1075,.T.);
#1077=ADVANCED_FACE('F691',(#1076),#1065,.T.);
#1078=CARTESIAN_POINT('',(0.,-29.,14.8333333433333));
#1079=DIRECTION('',(0.,1.,0.));
#1080=DIRECTION('',(-1.,0.,0.));
#1081=AXIS2_PLACEMENT_3D('',#1078,#1079,#1080);
#1082=PLANE('',#1081);
#1083=ORIENTED_EDGE('',*,*,#926,.F.);
#1084=DIRECTION('',(0.,0.,-1.));
#1085=VECTOR('',#1084,1.);
#1086=CARTESIAN_POINT('',(91.,-29.,14.8333333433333));
#1087=LINE('',#1086,#1085);
#1088=EDGE_CURVE('E513',#748,#917,#1087,.T.);
#1089=ORIENTED_EDGE('',*,*,#1088,.F.);
#1090=ORIENTED_EDGE('',*,*,#749,.T.);
#1091=ORIENTED_EDGE('',*,*,#1071,.T.);
#1092=EDGE_LOOP('',(#1083,#1089,#1090,#1091));
#1093=FACE_BOUND('',#1092,.T.);
#1094=ADVANCED_FACE('F606',(#1093),#1082,.T.);
#1095=CARTESIAN_POINT('',(0.,-0.999999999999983,14.8333333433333));
#1096=DIRECTION('',(0.,1.,0.));
#1097=DIRECTION('',(-1.,0.,0.));
#1098=AXIS2_PLACEMENT_3D('',#1095,#1096,#1097);
#1099=PLANE('',#1098);
#1100=ORIENTED_EDGE('',*,*,#876,.T.);
#1101=DIRECTION('',(0.,0.,-1.));
#1102=VECTOR('',#1101,1.);
#1103=CARTESIAN_POINT('',(89.,-0.999999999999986,14.8333333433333));
#1104=LINE('',#1103,#1102);
#1105=EDGE_CURVE('E514',#698,#875,#1104,.T.);
#1106=ORIENTED_EDGE('',*,*,#1105,.F.);
#1107=ORIENTED_EDGE('',*,*,#699,.F.);
#1108=DIRECTION('',(0.,0.,-1.));
#1109=VECTOR('',#1108,1.);
#1110=CARTESIAN_POINT('',(61.,-0.999999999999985,14.8333333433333));
#1111=LINE('',#1110,#1109);
#1112=EDGE_CURVE('E525',#696,#873,#1111,.T.);
#1113=ORIENTED_EDGE('',*,*,#1112,.T.);
#1114=EDGE_LOOP('',(#1100,#1106,#1107,#1113));
#1115=FACE_BOUND('',#1114,.T.);
#1116=ADVANCED_FACE('F911',(#1115),#1099,.F.);
#1117=CARTESIAN_POINT('',(89.,0.,14.8333333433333));
#1118=DIRECTION('',(-1.,0.,0.));
#1119=DIRECTION('',(0.,-1.,0.));
#1120=AXIS2_PLACEMENT_3D('',#1117,#1118,#1119);
#1121=PLANE('',#1120);
#1122=ORIENTED_EDGE('',*,*,#898,.F.);
#1123=DIRECTION('',(0.,0.,-1.));
#1124=VECTOR('',#1123,1.);
#1125=CARTESIAN_POINT('',(89.,-29.,14.8333333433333));
#1126=LINE('',#1125,#1124);
#1127=EDGE_CURVE('E534',#706,#891,#1126,.T.);
#1128=ORIENTED_EDGE('',*,*,#1127,.F.);
#1129=ORIENTED_EDGE('',*,*,#707,.T.);
#1130=ORIENTED_EDGE('',*,*,#1105,.T.);
#1131=EDGE_LOOP('',(#1122,#1128,#1129,#1130));
#1132=FACE_BOUND('',#1131,.T.);
#1133=ADVANCED_FACE('F920',(#1132),#1121,.T.);
#1134=CARTESIAN_POINT('',(0.,-29.,14.8333333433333));
#1135=DIRECTION('',(0.,1.,0.));
#1136=DIRECTION('',(-1.,0.,0.));
#1137=AXIS2_PLACEMENT_3D('',#1134,#1135,#1136);
#1138=PLANE('',#1137);
#1139=ORIENTED_EDGE('',*,*,#892,.F.);
#1140=DIRECTION('',(0.,0.,-1.));
#1141=VECTOR('',#1140,1.);
#1142=CARTESIAN_POINT('',(61.,-29.,14.8333333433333));
#1143=LINE('',#1142,#1141);
#1144=EDGE_CURVE('E529',#714,#883,#1143,.T.);
#1145=ORIENTED_EDGE('',*,*,#1144,.F.);
#1146=ORIENTED_EDGE('',*,*,#715,.T.);
#1147=ORIENTED_EDGE('',*,*,#1127,.T.);
#1148=EDGE_LOOP('',(#1139,#1145,#1146,#1147));
#1149=FACE_BOUND('',#1148,.T.);
#1150=ADVANCED_FACE('F740',(#1149),#1138,.T.);
#1151=CARTESIAN_POINT('',(0.,-1.,14.8333333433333));
#1152=DIRECTION('',(0.,1.,0.));
#1153=DIRECTION('',(-1.,0.,0.));
#1154=AXIS2_PLACEMENT_3D('',#1151,#1152,#1153);
#1155=PLANE('',#1154);
#1156=ORIENTED_EDGE('',*,*,#842,.T.);
#1157=DIRECTION('',(0.,0.,-1.));
#1158=VECTOR('',#1157,1.);
#1159=CARTESIAN_POINT('',(59.,-0.999999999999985,14.8333333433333));
#1160=LINE('',#1159,#1158);
#1161=EDGE_CURVE('E530',#664,#841,#1160,.T.);
#1162=ORIENTED_EDGE('',*,*,#1161,.F.);
#1163=ORIENTED_EDGE('',*,*,#665,.F.);
#1164=DIRECTION('',(0.,0.,-1.));
#1165=VECTOR('',#1164,1.);
#1166=CARTESIAN_POINT('',(31.,-0.999999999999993,14.8333333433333));
#1167=LINE('',#1166,#1165);
#1168=EDGE_CURVE('E541',#662,#839,#1167,.T.);
#1169=ORIENTED_EDGE('',*,*,#1168,.T.);
#1170=EDGE_LOOP('',(#1156,#1162,#1163,#1169));
#1171=FACE_BOUND('',#1170,.T.);
#1172=ADVANCED_FACE('F724',(#1171),#1155,.F.);
#1173=CARTESIAN_POINT('',(59.,0.,14.8333333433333));
#1174=DIRECTION('',(1.,0.,0.));
#1175=DIRECTION('',(0.,1.,0.));
#1176=AXIS2_PLACEMENT_3D('',#1173,#1174,#1175);
#1177=PLANE('',#1176);
#1178=ORIENTED_EDGE('',*,*,#864,.T.);
#1179=DIRECTION('',(0.,0.,-1.));
#1180=VECTOR('',#1179,1.);
#1181=CARTESIAN_POINT('',(59.,-29.,14.8333333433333));
#1182=LINE('',#1181,#1180);
#1183=EDGE_CURVE('E550',#672,#857,#1182,.T.);
#1184=ORIENTED_EDGE('',*,*,#1183,.F.);
#1185=ORIENTED_EDGE('',*,*,#673,.F.);
#1186=ORIENTED_EDGE('',*,*,#1161,.T.);
#1187=EDGE_LOOP('',(#1178,#1184,#1185,#1186));
#1188=FACE_BOUND('',#1187,.T.);
#1189=ADVANCED_FACE('F731',(#1188),#1177,.F.);
#1190=CARTESIAN_POINT('',(0.,-29.,14.8333333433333));
#1191=DIRECTION('',(0.,-1.,0.));
#1192=DIRECTION('',(1.,0.,0.));
#1193=AXIS2_PLACEMENT_3D('',#1190,#1191,#1192);
#1194=PLANE('',#1193);
#1195=ORIENTED_EDGE('',*,*,#858,.T.);
#1196=DIRECTION('',(0.,0.,-1.));
#1197=VECTOR('',#1196,1.);
#1198=CARTESIAN_POINT('',(31.,-29.,14.8333333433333));
#1199=LINE('',#1198,#1197);
#1200=EDGE_CURVE('E545',#680,#849,#1199,.T.);
#1201=ORIENTED_EDGE('',*,*,#1200,.F.);
#1202=ORIENTED_EDGE('',*,*,#681,.F.);
#1203=ORIENTED_EDGE('',*,*,#1183,.T.);
#1204=EDGE_LOOP('',(#1195,#1201,#1202,#1203));
#1205=FACE_BOUND('',#1204,.T.);
#1206=ADVANCED_FACE('F733',(#1205),#1194,.F.);
#1207=CARTESIAN_POINT('',(1.,0.,14.8333333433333));
#1208=DIRECTION('',(-1.,0.,0.));
#1209=DIRECTION('',(0.,-1.,0.));
#1210=AXIS2_PLACEMENT_3D('',#1207,#1208,#1209);
#1211=PLANE('',#1210);
#1212=ORIENTED_EDGE('',*,*,#952,.T.);
#1213=ORIENTED_EDGE('',*,*,#1000,.F.);
#1214=ORIENTED_EDGE('',*,*,#789,.F.);
#1215=ORIENTED_EDGE('',*,*,#1032,.T.);
#1216=EDGE_LOOP('',(#1212,#1213,#1214,#1215));
#1217=FACE_BOUND('',#1216,.T.);
#1218=ADVANCED_FACE('F738',(#1217),#1211,.F.);
#1219=CARTESIAN_POINT('',(91.,0.,14.8333333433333));
#1220=DIRECTION('',(1.,0.,0.));
#1221=DIRECTION('',(0.,1.,0.));
#1222=AXIS2_PLACEMENT_3D('',#1219,#1220,#1221);
#1223=PLANE('',#1222);
#1224=ORIENTED_EDGE('',*,*,#918,.F.);
#1225=ORIENTED_EDGE('',*,*,#1056,.F.);
#1226=ORIENTED_EDGE('',*,*,#755,.T.);
#1227=ORIENTED_EDGE('',*,*,#1088,.T.);
#1228=EDGE_LOOP('',(#1224,#1225,#1226,#1227));
#1229=FACE_BOUND('',#1228,.T.);
#1230=ADVANCED_FACE('F699',(#1229),#1223,.T.);
#1231=CARTESIAN_POINT('',(61.,0.,14.8333333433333));
#1232=DIRECTION('',(1.,0.,0.));
#1233=DIRECTION('',(0.,1.,0.));
#1234=AXIS2_PLACEMENT_3D('',#1231,#1232,#1233);
#1235=PLANE('',#1234);
#1236=ORIENTED_EDGE('',*,*,#884,.F.);
#1237=ORIENTED_EDGE('',*,*,#1112,.F.);
#1238=ORIENTED_EDGE('',*,*,#721,.T.);
#1239=ORIENTED_EDGE('',*,*,#1144,.T.);
#1240=EDGE_LOOP('',(#1236,#1237,#1238,#1239));
#1241=FACE_BOUND('',#1240,.T.);
#1242=ADVANCED_FACE('F974',(#1241),#1235,.T.);
#1243=CARTESIAN_POINT('',(31.,0.,14.8333333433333));
#1244=DIRECTION('',(-1.,0.,0.));
#1245=DIRECTION('',(0.,-1.,0.));
#1246=AXIS2_PLACEMENT_3D('',#1243,#1244,#1245);
#1247=PLANE('',#1246);
#1248=ORIENTED_EDGE('',*,*,#850,.T.);
#1249=ORIENTED_EDGE('',*,*,#1168,.F.);
#1250=ORIENTED_EDGE('',*,*,#687,.F.);
#1251=ORIENTED_EDGE('',*,*,#1200,.T.);
#1252=EDGE_LOOP('',(#1248,#1249,#1250,#1251));
#1253=FACE_BOUND('',#1252,.T.);
#1254=ADVANCED_FACE('F729',(#1253),#1247,.F.);
#1255=CLOSED_SHELL('',(#58,#98,#138,#169,#200,#240,#271,#302,#342,#373,#404,#444,#475,#506,#528,
#550,#572,#594,#616,#793,#970,#982,#1004,#1021,#1038,#1060,#1077,#1094,#1116,#1133,#1150,#1172,
#1189,#1206,#1218,#1230,#1242,#1254));
#1256=MANIFOLD_SOLID_BREP('B2',#1255);
#1257=ADVANCED_BREP_SHAPE_REPRESENTATION('',(#18,#1256),#14);
#1258=SHAPE_DEFINITION_REPRESENTATION(#9,#1257);
ENDSEC;
END-ISO-10303-21;
